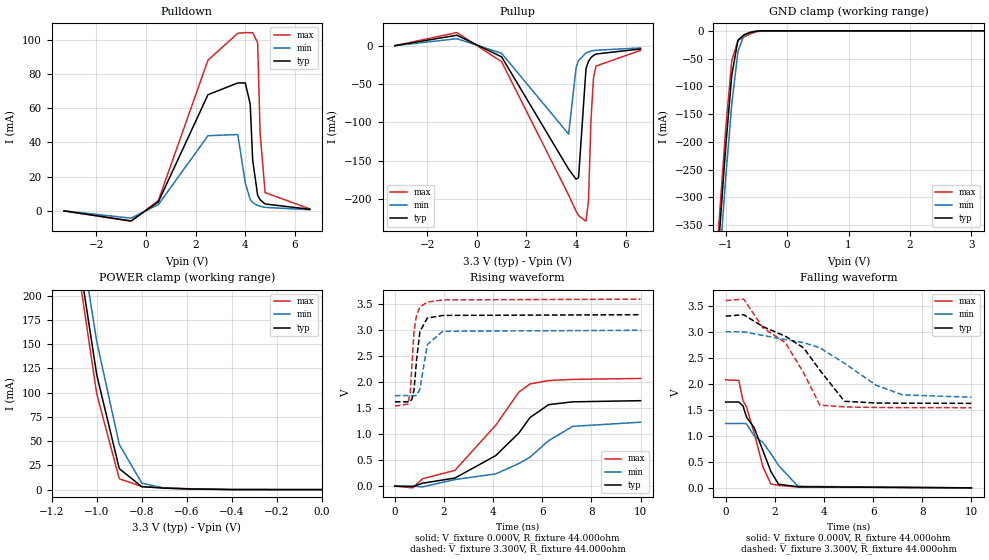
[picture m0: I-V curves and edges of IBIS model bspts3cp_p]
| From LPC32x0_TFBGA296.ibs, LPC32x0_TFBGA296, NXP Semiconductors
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| |   Rev 0.20 IBIS Model Design Automation Generation   |
| |   N O N - S I L I C O N   C O R R E L A T E D   |
| |   This IBIS [Model] is pre-Beta tactical support   |
| |  Note: this IBIS [Model] contains clamp curves generated   |
| |   through simulation which should not be relied upon   |
| bspts3cp
|   Bidirectional Pad 3v3
|   3state Output
|   Plain Input
|   3ns Slew Rate control
|   CMOS
|   Programmable between
|   - (p1=0, p2=1) plain input
|   - (p1=0, p2=0) with Pull Up
|   - (p1=1, p2=1) with Pull Down
|   - (p1=1, p2=0) with Repeater
|   Characterized at Core 1.2V and I/O 3.3V
| Plain input Mode (p1=0, p2=1)
[Model]   bspts3cp_p | of bspts3cp
Model_type   I/O
Polarity   Non-Inverting
Enable   Active-Low
|  Reciever Thresholds
Vinl   = 0.36V
Vinh   = 0.84V
| AC Test Load Conditions
Vref   = 0
Cref   = 1.2e-11
Rref   = 1000000000
Vmeas   = 0.6
| [Process Range]   typical   min   max
| C_comp edge width   400.000ps   400.000ps   400.000ps
| C_comp Tstrobe   40.000fs   40.000fs   40.000fs
C_comp   2.390pF   2.242pF   2.566pF
[Temperature Range]   25   125   -40
[Voltage Range]   3.30V   3.00V   3.60V
[GND Clamp Reference]   0.00V   0.00V   0.00V
[Pulldown Reference]   0.00V   0.00V   0.00V
[POWER Clamp Reference]   3.30V   3.00V   3.60V
[Pullup Reference]   3.30V   3.00V   3.60V
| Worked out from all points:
|   slope of the pulldown table from 0 to 0.495 V, typ, clamps not added: 97.1 ohm
|   slope of the pullup table from 0 to 0.495 V, typ, clamps not added: 59.3 ohm
|   GND clamp passes 1 mA (typ) near -0.51 V on its own axis
|   POWER clamp passes 1 mA (typ) near -0.63 V on its own axis
|   rising waveform, V_fixture 0.000V, R_fixture 44.000ohm: 20-80 % time 2.13ns typ, 2.37ns min, 2.1ns max; typ from 0 V to 1.65 V
|   falling waveform, V_fixture 0.000V, R_fixture 44.000ohm: 20-80 % time 928ps typ, 1.23ns min, 791ps max; typ from 1.65 V to 0 V
|   rising waveform, V_fixture 3.300V, R_fixture 44.000ohm: 20-80 % time 210ps typ, 252ps min, 185ps max; typ from 1.62 V to 3.3 V
|   falling waveform, V_fixture 3.300V, R_fixture 44.000ohm: 20-80 % time 2.17ns typ, 2.52ns min, 2.04ns max; typ from 3.3 V to 1.62 V
[GND Clamp]
| ref voltage   0.00V   0.00V   0.00V
|   Voltage   I(typ)   I(min)   I(max)
-3.3V     -4.198A    -4.223A    -4.188A
-1.2V     -526mA     -577.5mA   -497.2mA
-1.1V     -363.6mA   -417.9mA   -332.6mA
-1V       -210.1mA   -266.3mA   -177.3mA
-900mV    -79.7mA    -131.5mA   -53.27mA
-800mV    -16.73mA   -37.37mA   -17.76mA
-700mV    -7.134mA   -7.247mA   -10.88mA
-600mV    -2.975mA   -2.186mA   -5.408mA
-500mV    -676.3uA   -558.4uA   -1.581mA
-400mV    -60.83uA   -85.23uA   -138.3uA
3.2V      712.7pA    549nA      572.1pA
[Power Clamp]   | Vtable = Vcc - Vpad
| ref voltage   3.30V   3.00V   3.60V
|   Voltage   I(typ)   I(min)   I(max)
-3.3V     4.52A      4.504A     4.537A
-1.1V     269.9mA    299.6mA    255.3mA
-1V       118.1mA    152.4mA    98.46mA
-900mV    21.59mA    46.52mA    11.18mA
-800mV    2.991mA    6.661mA    3.207mA
-700mV    1.495mA    1.535mA    1.933mA
-600mV    740.8uA    686.9uA    976.4uA
-400mV    40.41uA    69.77uA    40.29uA
0V        755.1pA    5.591nA    627.9pA
[Pulldown]
| ref voltage   0.00V   0.00V   0.00V
|   Voltage   I(typ)   I(min)   I(max)
-3.3V     -80.68uA   -69.9uA    -74.32uA
-600mV    -5.92mA    -4.329mA   -6.173mA
500mV     5.147mA    3.568mA    5.923mA
2.5V      67.8mA     43.83mA    87.99mA
3.7V      74.65mA    44.53mA    103.7mA
4V        74.69mA    16.44mA    104.1mA
4.2V      62.37mA    6.515mA    104mA
4.3V      29.48mA    4.769mA    104mA
4.5V      9.068mA    3.068mA    98.16mA
4.6V      6.413mA    2.587mA    45.13mA
4.8V      3.956mA    1.96mA     10.6mA
6.6V      844.8uA    597.5uA    1.056mA
[Pullup]   | Vtable = Vcc - Vpad
| ref voltage   3.30V   3.00V   3.60V
|   Voltage   I(typ)   I(min)   I(max)
-3.3V     39.4uA     37.84uA    38.83uA
-800mV    13.66mA    9.122mA    17.15mA
1V        -14.52mA   -9.936mA   -20.86mA
3.7V      -161.3mA   -115.5mA   -195.1mA
4V        -174.4mA   -29.02mA   -216.2mA
4.1V      -172.4mA   -19.17mA   -221.9mA
4.4V      -30.01mA   -9.422mA   -229.4mA
4.5V      -20.39mA   -8.135mA   -202.5mA
4.6V      -15.6mA    -7.195mA   -97.89mA
4.7V      -12.75mA   -6.48mA    -42.98mA
4.8V      -10.87mA   -5.92mA    -26.67mA
6.6V      -4.278mA   -2.929mA   -6.056mA
[Ramp]
R_load   = 44.000ohm
|   dV/dt(typ)   dV/dt(min)   dV/dt(max)
dV/dt_r   1.000V/2.135ns   750.814mV/2.380ns   1.259V/2.105ns
dV/dt_f   1.022V/2.190ns   769.258mV/2.465ns   1.253V/2.030ns
[Rising Waveform]  | cubic spline decimation from 2001 points
V_fixture   = 0.000V
R_fixture   = 44.000ohm
|   Time   V(typ)   V(min)   V(max)
0s        20.67nV    394.6nV    10.71nV
730ps     -10.45mV   1.455mV    -33.19mV
1.125ns   55.98mV    -15.06mV   142.9mV
2.445ns   155.8mV    126.8mV    303.1mV
4.105ns   587.7mV    236.2mV    1.172V
5.05ns    1.024V     436mV      1.813V
5.5ns     1.321V     557.4mV    1.967V
6.26ns    1.569V     876.4mV    2.033V
7.24ns    1.623V     1.151V     2.055V
10ns      1.645V     1.231V     2.073V
[Falling Waveform]  | cubic spline decimation from 2001 points
V_fixture   = 0.000V
R_fixture   = 44.000ohm
|   Time   V(typ)   V(min)   V(max)
0s        1.649V     1.237V     2.077V
535ps     1.65V      1.237V     2.064V
705ps     1.575V     1.239V     1.675V
850ps     1.357V     1.23V      1.551V
1.16ns    1.155V     999mV      1.058V
1.515ns   716.4mV    873.1mV    403.1mV
1.84ns    314.7mV    659.4mV    75.27mV
2.15ns    70.6mV     432.5mV    46.06mV
2.94ns    20.57mV    29.74mV    17.35mV
10ns      25.19uV    52.97uV    20.87uV
[Rising Waveform]  | cubic spline decimation from 2001 points
V_fixture   = 3.300V
V_fixture_min = 3.000V
V_fixture_max = 3.600V
R_fixture   = 44.000ohm
|   Time   V(typ)   V(min)   V(max)
0s        1.624V     1.742V     1.54V
535ps     1.623V     1.743V     1.58V
630ps     1.628V     1.743V     1.809V
700ps     1.683V     1.742V     2.365V
780ps     1.852V     1.739V     2.977V
885ps     2.431V     1.748V     3.293V
1.02ns    2.974V     1.867V     3.448V
1.32ns    3.235V     2.722V     3.542V
1.95ns    3.286V     2.982V     3.585V
10ns      3.3V       3V         3.6V
[Falling Waveform]  | cubic spline decimation from 2001 points
V_fixture   = 3.300V
V_fixture_min = 3.000V
V_fixture_max = 3.600V
R_fixture   = 44.000ohm
|   Time   V(typ)   V(min)   V(max)
0s        3.3V       3V         3.6V
735ps     3.327V     2.998V     3.627V
1.515ns   3.099V     2.93V      3.078V
2.435ns   2.912V     2.849V     2.788V
3.17ns    2.691V     2.792V     2.212V
3.83ns    2.263V     2.692V     1.59V
4.835ns   1.663V     2.394V     1.556V
6.13ns    1.631V     1.97V      1.545V
7.2ns     1.627V     1.787V     1.542V
10ns      1.624V     1.742V     1.54V
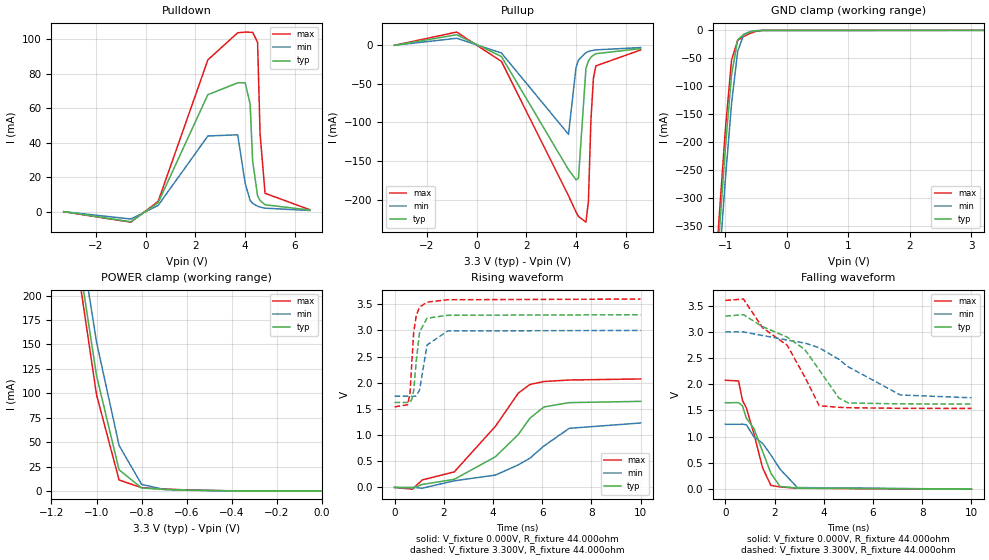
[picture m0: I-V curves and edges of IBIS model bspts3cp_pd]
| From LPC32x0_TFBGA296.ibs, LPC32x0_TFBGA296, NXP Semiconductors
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| |   Rev 0.20 IBIS Model Design Automation Generation   |
| |   N O N - S I L I C O N   C O R R E L A T E D   |
| |   This IBIS [Model] is pre-Beta tactical support   |
| |  Note: this IBIS [Model] contains clamp curves generated   |
| |   through simulation which should not be relied upon   |
| bspts3cp
|   Bidirectional Pad 3v3
|   3state Output
|   Plain Input
|   3ns Slew Rate control
|   CMOS
|   Programmable between
|   - (p1=0, p2=1) plain input
|   - (p1=0, p2=0) with Pull Up
|   - (p1=1, p2=1) with Pull Down
|   - (p1=1, p2=0) with Repeater
|   Characterized at Core 1.2V and I/O 3.3V
| Pull Down Mode (p1=1, p2=1)
[Model]   bspts3cp_pd | of bspts3cp
Model_type   I/O
Polarity   Non-Inverting
Enable   Active-Low
|  Reciever Thresholds
Vinl   = 0.36V
Vinh   = 0.84V
| AC Test Load Conditions
Vref   = 0
Cref   = 1.2e-11
Rref   = 1000000000
Vmeas   = 0.6
| [Process Range]   typical   min   max
| C_comp edge width   400.000ps   400.000ps   400.000ps
| C_comp Tstrobe   40.000fs   40.000fs   40.000fs
C_comp   2.389pF   2.242pF   2.565pF
[Temperature Range]   25   125   -40
[Voltage Range]   3.30V   3.00V   3.60V
[GND Clamp Reference]   0.00V   0.00V   0.00V
[Pulldown Reference]   0.00V   0.00V   0.00V
[POWER Clamp Reference]   3.30V   3.00V   3.60V
[Pullup Reference]   3.30V   3.00V   3.60V
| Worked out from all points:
|   slope of the pulldown table from 0 to 0.495 V, typ, clamps not added: 97.1 ohm
|   slope of the pullup table from 0 to 0.495 V, typ, clamps not added: 59.3 ohm
|   GND clamp passes 1 mA (typ) near -0.51 V on its own axis
|   POWER clamp passes 1 mA (typ) near -0.63 V on its own axis
|   rising waveform, V_fixture 0.000V, R_fixture 44.000ohm: 20-80 % time 2.13ns typ, 2.37ns min, 2.1ns max; typ from 0 V to 1.64 V
|   falling waveform, V_fixture 0.000V, R_fixture 44.000ohm: 20-80 % time 927ps typ, 1.23ns min, 791ps max; typ from 1.65 V to 0 V
|   rising waveform, V_fixture 3.300V, R_fixture 44.000ohm: 20-80 % time 211ps typ, 252ps min, 185ps max; typ from 1.62 V to 3.3 V
|   falling waveform, V_fixture 3.300V, R_fixture 44.000ohm: 20-80 % time 2.17ns typ, 2.51ns min, 2.04ns max; typ from 3.3 V to 1.62 V
[GND Clamp]
| ref voltage   0.00V   0.00V   0.00V
|   Voltage   I(typ)   I(min)   I(max)
-3.3V     -4.198A    -4.223A    -4.188A
-1.2V     -526mA     -577.5mA   -497.2mA
-1.1V     -363.6mA   -417.9mA   -332.6mA
-1V       -210.1mA   -266.3mA   -177.3mA
-900mV    -79.71mA   -131.5mA   -53.29mA
-800mV    -16.76mA   -37.38mA   -17.81mA
-700mV    -7.164mA   -7.263mA   -10.92mA
-600mV    -3.002mA   -2.202mA   -5.445mA
-500mV    -699uA     -571.9uA   -1.612mA
-400mV    -79uA      -96.04uA   -163.6uA
3.2V      50.82uA    25.42uA    83.99uA
[Power Clamp]   | Vtable = Vcc - Vpad
| ref voltage   3.30V   3.00V   3.60V
|   Voltage   I(typ)   I(min)   I(max)
-3.3V     4.52A      4.504A     4.537A
-1.1V     269.9mA    299.6mA    255.3mA
-1V       118.1mA    152.5mA    98.49mA
-900mV    21.63mA    46.53mA    11.26mA
-800mV    3.041mA    6.684mA    3.29mA
-700mV    1.546mA    1.559mA    2.017mA
-600mV    791.6uA    711.8uA    1.06mA
-400mV    91.28uA    94.64uA    124.4uA
0V        50.84uA    24.87uA    84.1uA
[Pulldown]
| ref voltage   0.00V   0.00V   0.00V
|   Voltage   I(typ)   I(min)   I(max)
-3.3V     -80.68uA   -69.9uA    -74.32uA
-600mV    -5.92mA    -4.329mA   -6.172mA
500mV     5.147mA    3.568mA    5.922mA
2.5V      67.8mA     43.83mA    87.99mA
3.7V      74.65mA    44.53mA    103.7mA
4V        74.69mA    16.44mA    104.1mA
4.2V      62.38mA    6.515mA    104mA
4.3V      29.49mA    4.769mA    104mA
4.5V      9.069mA    3.068mA    98.17mA
4.6V      6.414mA    2.587mA    45.15mA
4.8V      3.956mA    1.96mA     10.6mA
6.6V      844.9uA    597.5uA    1.056mA
[Pullup]   | Vtable = Vcc - Vpad
| ref voltage   3.30V   3.00V   3.60V
|   Voltage   I(typ)   I(min)   I(max)
-3.3V     39.4uA     37.84uA    38.83uA
-800mV    13.66mA    9.122mA    17.15mA
1V        -14.52mA   -9.936mA   -20.86mA
3.7V      -161.3mA   -115.5mA   -195.1mA
4V        -174.4mA   -29.02mA   -216.2mA
4.1V      -172.4mA   -19.17mA   -221.9mA
4.4V      -30.01mA   -9.422mA   -229.4mA
4.5V      -20.39mA   -8.135mA   -202.5mA
4.6V      -15.6mA    -7.195mA   -97.92mA
4.7V      -12.75mA   -6.48mA    -42.98mA
4.8V      -10.87mA   -5.92mA    -26.67mA
6.6V      -4.278mA   -2.929mA   -6.056mA
[Ramp]
R_load   = 44.000ohm
|   dV/dt(typ)   dV/dt(min)   dV/dt(max)
dV/dt_r   1.000V/2.135ns   750.584mV/2.380ns   1.258V/2.105ns
dV/dt_f   1.021V/2.190ns   769.127mV/2.460ns   1.253V/2.025ns
[Rising Waveform]  | cubic spline decimation from 2001 points
V_fixture   = 0.000V
R_fixture   = 44.000ohm
|   Time   V(typ)   V(min)   V(max)
0s        20.64nV    394.3nV    10.69nV
730ps     -10.5mV    1.461mV    -33.3mV
1.125ns   56mV       -15.12mV   142.8mV
2.43ns    154.9mV    126.6mV    297.5mV
4.105ns   587.6mV    236.2mV    1.171V
5.03ns    1.011V     430.9mV    1.801V
5.5ns     1.321V     557.4mV    1.966V
6.07ns    1.537V     791.3mV    2.023V
7.1ns     1.62V      1.129V     2.052V
10ns      1.644V     1.231V     2.072V
[Falling Waveform]  | cubic spline decimation from 2001 points
V_fixture   = 0.000V
R_fixture   = 44.000ohm
|   Time   V(typ)   V(min)   V(max)
0s        1.648V     1.237V     2.076V
535ps     1.649V     1.237V     2.063V
695ps     1.589V     1.238V     1.691V
850ps     1.356V     1.229V     1.551V
1.16ns    1.155V     998.7mV    1.057V
1.515ns   716mV      872.9mV    403mV
1.85ns    303.6mV    651.8mV    72.49mV
2.22ns    52.46mV    382.4mV    42.68mV
2.925ns   20.87mV    31.01mV    17.6mV
10ns      25.08uV    52.74uV    20.78uV
[Rising Waveform]  | cubic spline decimation from 2001 points
V_fixture   = 3.300V
V_fixture_min = 3.000V
V_fixture_max = 3.600V
R_fixture   = 44.000ohm
|   Time   V(typ)   V(min)   V(max)
0s        1.623V     1.742V     1.539V
535ps     1.623V     1.742V     1.579V
630ps     1.627V     1.742V     1.808V
700ps     1.682V     1.741V     2.363V
780ps     1.851V     1.739V     2.974V
885ps     2.43V      1.748V     3.288V
1.02ns    2.971V     1.866V     3.444V
1.32ns    3.232V     2.721V     3.539V
2.16ns    3.288V     2.988V     3.585V
10ns      3.299V     2.999V     3.598V
[Falling Waveform]  | cubic spline decimation from 2001 points
V_fixture   = 3.300V
V_fixture_min = 3.000V
V_fixture_max = 3.600V
R_fixture   = 44.000ohm
|   Time   V(typ)   V(min)   V(max)
0s        3.299V     2.999V     3.598V
735ps     3.326V     2.997V     3.624V
1.515ns   3.097V     2.929V     3.075V
2.515ns   2.897V     2.842V     2.742V
3.225ns   2.664V     2.786V     2.141V
3.815ns   2.272V     2.695V     1.591V
4.615ns   1.736V     2.474V     1.56V
5ns       1.643V     2.33V      1.553V
7.115ns   1.626V     1.795V     1.541V
10ns      1.624V     1.742V     1.539V
